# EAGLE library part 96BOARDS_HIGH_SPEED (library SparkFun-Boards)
96 BOARDS high speed connectors. 2 variants: 1. "TOP" goes on the top of the board, called a "Receptacale" in the parlance. Candidate parts would be FCI/Bergquist 61082-061409LF 2. "BOTTOM" goes on the bottom of a board. Candidate parts would be FCI 61083-063409LF for 7mm board-to-board clearance, or 61083-064409LF for 8mm clearance. If you're placing one on the bottom of a board, take care to mind the pin-1 orientation.

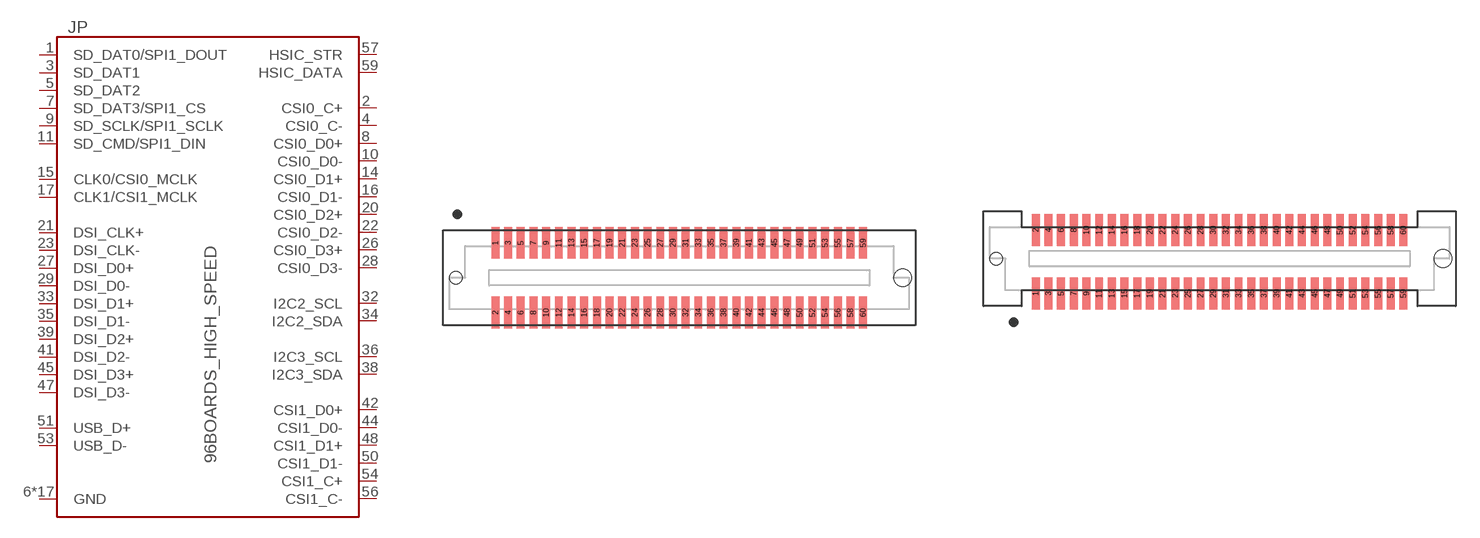
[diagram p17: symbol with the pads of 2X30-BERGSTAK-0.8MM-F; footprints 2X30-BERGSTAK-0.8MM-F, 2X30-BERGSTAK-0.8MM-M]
Designator prefix JP

## 96BOARDS_HIGH_SPEEDBOTTOM (VALUE: 96BOARDS HIGH SPEED)  [2X30-BERGSTAK-0.8MM-F]
1  SD_DAT0/SPI1_DOUT
2  CSI0_C+
3  SD_DAT1
4  CSI0_C-
5  SD_DAT2
6  GND
7  SD_DAT3/SPI1_CS
8  CSI0_D0+
9  SD_SCLK/SPI1_SCLK
10  CSI0_D0-
11  SD_CMD/SPI1_DIN
12  GND
13  GND
14  CSI0_D1+
15  CLK0/CSI0_MCLK
16  CSI0_D1-
17  CLK1/CSI1_MCLK
18  GND
19  GND
20  CSI0_D2+
21  DSI_CLK+
22  CSI0_D2-
23  DSI_CLK-
24  GND
25  GND
26  CSI0_D3+
27  DSI_D0+
28  CSI0_D3-
29  DSI_D0-
30  GND
31  GND
32  I2C2_SCL
33  DSI_D1+
34  I2C2_SDA
35  DSI_D1-
36  I2C3_SCL
37  GND
38  I2C3_SDA
39  DSI_D2+
40  GND
41  DSI_D2-
42  CSI1_D0+
43  GND
44  CSI1_D0-
45  DSI_D3+
46  GND
47  DSI_D3-
48  CSI1_D1+
49  GND
50  CSI1_D1-
51  USB_D+
52  GND
53  USB_D-
54  CSI1_C+
55  GND
56  CSI1_C-
57  HSIC_STR
58  GND
59  HSIC_DATA

## 96BOARDS_HIGH_SPEEDTOP (VALUE: 96 BOARDS HIGH SPEED)  [2X30-BERGSTAK-0.8MM-M]
Pads as for 2X30-BERGSTAK-0.8MM-F

## Footprint 2X30-BERGSTAK-0.8MM-F (pad centres in mm)
96BOARDS High Speed connector For video & camera interfaces Part as drawn in the for the part: - FCI 61083-063402PLF for 7mm stack height or - FCI 61083-064402PLF for 8mm stack
smd 0.5 x 2: 1 -11.6,2.2; 2 -11.6,-2.2; 3 -10.8,2.2; 4 -10.8,-2.2; 5 -10,2.2; 6 -10,-2.2; 7 -9.2,2.2; 8 -9.2,-2.2; 9 -8.4,2.2; 10 -8.4,-2.2; 11 -7.6,2.2; 12 -7.6,-2.2; 13 -6.8,2.2; 14 -6.8,-2.2; 15 -6,2.2; 16 -6,-2.2; 17 -5.2,2.2; 18 -5.2,-2.2; 19 -4.4,2.2; 20 -4.4,-2.2; 21 -3.6,2.2; 22 -3.6,-2.2; 23 -2.8,2.2; 24 -2.8,-2.2; 25 -2,2.2; 26 -2,-2.2; 27 -1.2,2.2; 28 -1.2,-2.2; 29 -0.4,2.2; 30 -0.4,-2.2; 31 0.4,2.2; 32 0.4,-2.2; 33 1.2,2.2; 34 1.2,-2.2; 35 2,2.2; 36 2,-2.2; 37 2.8,2.2; 38 2.8,-2.2; 39 3.6,2.2; 40 3.6,-2.2; 41 4.4,2.2; 42 4.4,-2.2; 43 5.2,2.2; 44 5.2,-2.2; 45 6,2.2; 46 6,-2.2; 47 6.8,2.2; 48 6.8,-2.2; 49 7.6,2.2; 50 7.6,-2.2; 51 8.4,2.2; 52 8.4,-2.2; 53 9.2,2.2; 54 9.2,-2.2; 55 10,2.2; 56 10,-2.2; 57 10.8,2.2; 58 10.8,-2.2; 59 11.6,2.2; 60 11.6,-2.2
hole 0.8 at -14.1,0
hole 1.12 at 14.1,0

## Footprint 2X30-BERGSTAK-0.8MM-M (pad centres in mm)
smd 0.5 x 2: 1 -11.6,-2.2; 2 -11.6,1.8; 3 -10.8,-2.2; 4 -10.8,1.8; 5 -10,-2.2; 6 -10,1.8; 7 -9.2,-2.2; 8 -9.2,1.8; 9 -8.4,-2.2; 10 -8.4,1.8; 11 -7.6,-2.2; 12 -7.6,1.8; 13 -6.8,-2.2; 14 -6.8,1.8; 15 -6,-2.2; 16 -6,1.8; 17 -5.2,-2.2; 18 -5.2,1.8; 19 -4.4,-2.2; 20 -4.4,1.8; 21 -3.6,-2.2; 22 -3.6,1.8; 23 -2.8,-2.2; 24 -2.8,1.8; 25 -2,-2.2; 26 -2,1.8; 27 -1.2,-2.2; 28 -1.2,1.8; 29 -0.4,-2.2; 30 -0.4,1.8; 31 0.4,-2.2; 32 0.4,1.8; 33 1.2,-2.2; 34 1.2,1.8; 35 2,-2.2; 36 2,1.8; 37 2.8,-2.2; 38 2.8,1.8; 39 3.6,-2.2; 40 3.6,1.8; 41 4.4,-2.2; 42 4.4,1.8; 43 5.2,-2.2; 44 5.2,1.8; 45 6,-2.2; 46 6,1.8; 47 6.8,-2.2; 48 6.8,1.8; 49 7.6,-2.2; 50 7.6,1.8; 51 8.4,-2.2; 52 8.4,1.8; 53 9.2,-2.2; 54 9.2,1.8; 55 10,-2.2; 56 10,1.8; 57 10.8,-2.2; 58 10.8,1.8; 59 11.6,-2.2; 60 11.6,1.8
hole 0.8 at -14.1,0
hole 1.12 at 14.1,0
